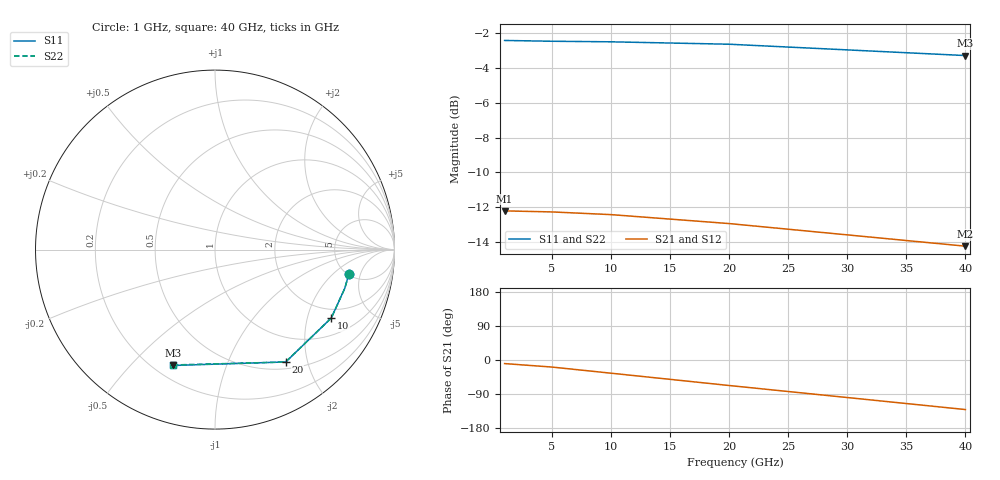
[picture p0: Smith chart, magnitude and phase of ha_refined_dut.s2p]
! Generated by circuitRF - EM: Palace
! circuitRF-EM setup: ha_refined_dut Palace
! circuitRF-EM layout: ha_refined_dut.c3d
! circuitRF-EM written: 2026-11-04 15:50:18Z
! circuitRF-EM geometry: 7451b118e5080301
! circuitRF-EM mesh: 5f7b40af5b6dd3d3
! circuitRF-EM ports: 5c7d998361b0986e
! circuitRF-EM model: Palace 0.18.1 (0dc74cd, schema 1-7-0)
! Port[1] = P1
! Port[2] = P2
! circuitRF-EM port 1: 'port/1' from 'airbox/zmin' to 'metal1', wave (mode 1), 50 Ohm: Palace's S is referred to the mode's own impedance Z_PV, renormalised here to 50 Ohm; reference plane 0 um into the structure from the port face
! circuitRF-EM port 2: 'port/2' from 'airbox/zmin' to 'metal2', wave (mode 1), 50 Ohm: Palace's S is referred to the mode's own impedance Z_PV, renormalised here to 50 Ohm; reference plane 0 um into the structure from the port face
! circuitRF-EM 3D mesh: 23,307 elements initially, 23,307 finally, 0 adaptive pass(es), element order 2
! circuitRF-EM 3D operating temperature: 20 C
! circuitRF-EM 3D run: preset Standard; 23307 -> 23307 tetrahedra; 162064 unknowns; 0 refinement pass(es); 5 frequency sample(s)
! circuitRF-EM 3D run cost: wall 169 s; Palace peak memory 2.8 GB
! circuitRF-EM 3D DC row: circuitRF conduction solve of the conductors, 472 elements, 0.21 s; ports as terminal pairs
! circuitRF-EM: re-running the EM setup rewrites this file. If circuitRF reports it as stale, the layout's cross-section changed after this file was written.
# GHz S RI R 50
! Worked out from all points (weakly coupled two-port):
!   5 points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, 1 GHz to 40 GHz, reference 50 ohm
!   highest |S21| = -12.22 dB at 1 GHz (marker M1); lowest = -14.3 dB at 40 GHz (marker M2)
!   lowest |S11| = -3.3 dB at 40 GHz (marker M3), VSWR 5.37, Z = 13.7 - j33.4 ohm
!   |S11| at or under -10 dB: nowhere
!   |S22| runs from -3.3 to -2.4 dB; largest |S21 - S12| = 2.5e-06
!   S11 on the Smith chart (normalised r, x): 1 GHz: 5.18, -3.25; 10 GHz: 1.62, -2.83; 20 GHz: 0.60, -1.65; 40 GHz: 0.27, -0.67
1  0.7466 -0.1335  0.2415 -0.0403  0.2415 -0.0403  0.7469 -0.1335
5  0.7227 -0.2165  0.2305 -0.0776  0.2305 -0.0776  0.7229 -0.2168
10  0.648 -0.3809  0.1962 -0.1363  0.1962 -0.1363  0.6478 -0.3814
20  0.3942 -0.6259  0.0869 -0.2077  0.0869 -0.2077  0.393 -0.6264
40  -0.2324 -0.6456  -0.1265 -0.1468  -0.1265 -0.1468  -0.2348 -0.6428
